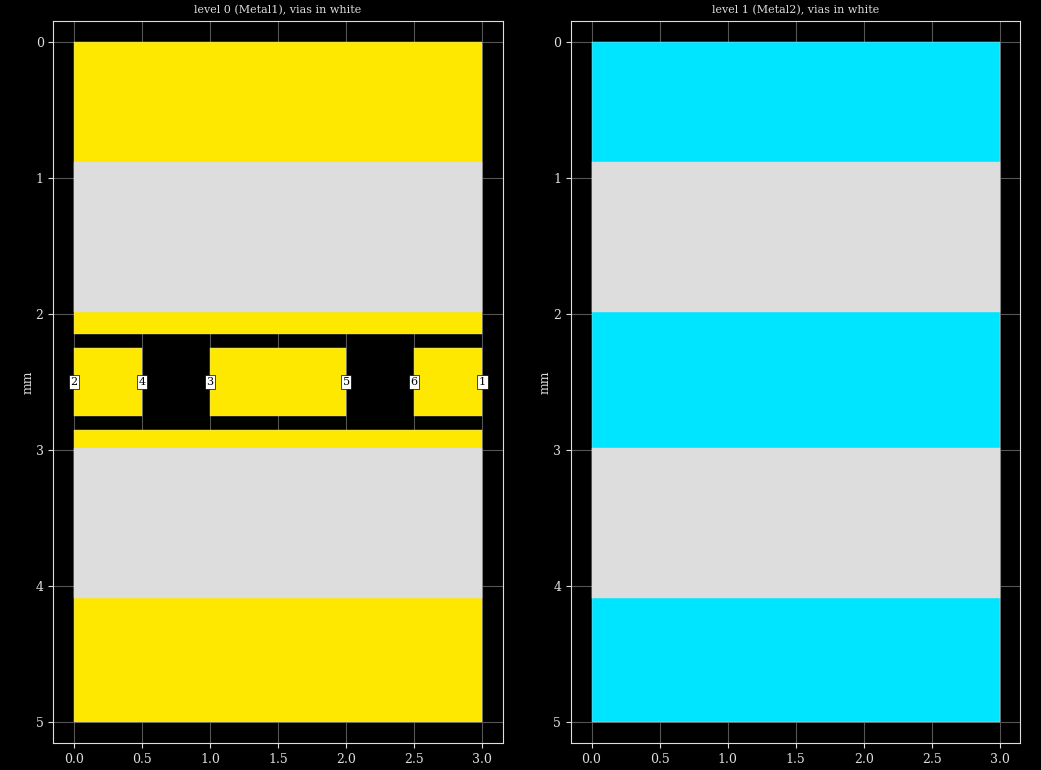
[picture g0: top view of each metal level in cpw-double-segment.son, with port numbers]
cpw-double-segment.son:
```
FTYP SONPROJ 17 ! Sonnet Project File
VER 17.52.2
HEADER
LIC antikernel2.1.48685 3cfdfeabd719 havequick azonenberg
DAT 12/26/2019 12:14:46
BUILT_BY_CREATED xgeom 16.56 07/03/2018 15:05:41
BUILT_BY_SAVED sonnet 17.52.2
MDATE 12/26/2019 12:14:17
HDATE 12/26/2019 12:14:17
ANN _gk:
ANN 
ANN disabled symmetry
ANN dleted lower air layer and internal groundplane
ANN using analysis box bottom cover as groundplane
ANN assigned the via rectangles to the Via1 tech layer
ANN stretched the via ends to connect with the east and west boxwalls
ANN made via rectangles symmetrical about Y
ANN defined new Copper_Gnd normal metal type
ANN changed box bottom cover from freespace to Copper_Gnd
ANN 
ANN _gk2:
ANN 
ANN per Matt crash is caused by incorrect port handling with symmetry, component below the line of symmetry, and ABS.
ANN most efficient workaround is to delete the resistor components below the line of symmetry
ANN then symmetry can still be used
ANN this is what i did in this model
ANN 
ANN 
ANN 
END HEADER
DIM
ANG DEG
CAP PF
CON /OH
FREQ GHZ
IND NH
LNG MM
RES OH
END DIM
CONTROL
VARSWP
OPTIONS  -dj
SPEED 0
CACHE_ABS 1
Q_ACC N
END CONTROL
GEO
SYM
TMET "Free Space" 0 FREESPACE 376.7303136 0 0 0
BMET "Copper_Gnd" 2 NOR 58000000 0 0.035 
MET "Copper" 1 TMM 58000000 0.5 0.035 3
BOX 2 3 5 240 400 20 0
      1 1 1 0 0 0 0 "Air"
      0.508 3.66 1 0.0037 0 0 0 "Rogers RO4350B"
      1 1 1 0 0 0 0 "Air"
TECHLAY METAL Metal1 <UNSPECIFIED> -2 0 
0 0 0 N 0 1 1 100 100 0 0 0 Y
END
END
TECHLAY VIA Via1 <UNSPECIFIED> -4 0 
VIA POLYGON
0 0 -1 N 0 1 1 100 100 0 0 0 Y
TOLEVEL 1 RING NOCOVERS
END
END
TECHLAY METAL Metal2 <UNSPECIFIED> -3 0 
1 0 -1 N 0 1 1 100 100 0 0 0 Y
END
END
LORGN 0 250 U 
POR1 CUP Auto
SIMPLE Y
GNDREF AUTO
TERMW FEED
POLY 660 1
3
3 50 0 0 0 1 2.5 
CUPGRP "Auto" LOCAL
ID 662
END
POR1 CUP Auto
SIMPLE Y
GNDREF AUTO
TERMW FEED
POLY 660 1
1
5 50 0 0 0 2 2.5 
CUPGRP "Auto" LOCAL
ID 664
END
POR1 BOX
POLY 665 1
3
2 50 0 0 0 0 2.5 
POR1 CUP Auto
SIMPLE Y
GNDREF AUTO
TERMW FEED
POLY 665 1
1
4 50 0 0 0 0.5 2.5 
CUPGRP "Auto" LOCAL
ID 668
END
POR1 BOX
POLY 669 1
1
1 50 0 0 0 3 2.5 
POR1 CUP Auto
SIMPLE Y
GNDREF AUTO
TERMW FEED
POLY 669 1
3
6 50 0 0 0 2.5 2.5 
CUPGRP "Auto" LOCAL
ID 673
END
NUM 8
0 5 0 N 658 1 1 100 100 0 0 0 Y
TLAYNAM Metal1 INH
0 0
3 0
3 2.15
0 2.15
0 0
END
0 5 0 N 659 1 1 100 100 0 0 0 Y
TLAYNAM Metal1 INH
0 2.85
3 2.85
3 5
0 5
0 2.85
END
0 5 0 N 660 1 1 100 100 0 0 0 Y
TLAYNAM Metal1 INH
1 2.25
2 2.25
2 2.75
1 2.75
1 2.25
END
0 5 0 N 665 1 1 100 100 0 0 0 Y
TLAYNAM Metal1 INH
0 2.25
0.5 2.25
0.5 2.75
0 2.75
0 2.25
END
0 5 0 N 669 1 1 100 100 0 0 0 Y
TLAYNAM Metal1 INH
2.5 2.25
3 2.25
3 2.75
2.5 2.75
2.5 2.25
END
VIA POLYGON
0 5 -1 N 675 1 1 100 100 0 0 0 Y
TOLEVEL 1 RING NOCOVERS
TLAYNAM Via1 INH
0 2.9875
3 2.9875
3 4.0875
0 4.0875
0 2.9875
END
VIA POLYGON
0 5 -1 N 676 1 1 100 100 0 0 0 Y
TOLEVEL 1 RING NOCOVERS
TLAYNAM Via1 INH
0 0.8875
3 0.8875
3 1.9875
0 1.9875
0 0.8875
END
1 5 -1 N 679 1 1 100 100 0 0 0 Y
TLAYNAM Metal2 INH
0 0
3 0
3 5
0 5
0 0
END
END GEO
OPT
MAX 100
END OPT
VARSWP
ENABLED Y
FREQ Y AY ABS_ENTRY 0.1 10.0 -1 300 
END
END VARSWP
FILEOUT
FOLDER .
END FILEOUT
```
